VERSION 5.8 ;
BUSBITCHARS "[]" ;
DIVIDERCHAR "/" ;
UNITS
    DATABASE MICRONS 1000 ;
END UNITS

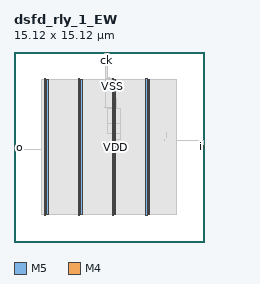
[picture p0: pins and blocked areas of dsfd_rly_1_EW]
MACRO dsfd_rly_1_EW
  FOREIGN dsfd_rly_1_EW 0 0 ;
  CLASS BLOCK ;
  SIZE 15.12 BY 15.12 ;
  PIN ck
    DIRECTION INPUT ;
    USE SIGNAL ;
    PORT
      LAYER M5 ;
        RECT  7.344 15.036 7.368 15.12 ;
    END
  END ck
  PIN i
    DIRECTION INPUT ;
    USE SIGNAL ;
    PORT
      LAYER M4 ;
        RECT  15.036 7.536 15.12 7.56 ;
    END
    PORT
      LAYER M4 ;
        RECT  15.001 7.536 15.084 7.656 ;
    END
  END i
  PIN o
    DIRECTION OUTPUT ;
    USE SIGNAL ;
    PORT
      LAYER M4 ;
        RECT  0 7.536 0.084 7.56 ;
    END
    PORT
      LAYER M4 ;
        RECT  0.06 7.536 0.137 7.56 ;
    END
  END o
  PIN rs
    DIRECTION INPUT ;
    USE SIGNAL ;
    PORT
      LAYER M5 ;
        RECT  7.44 15.036 7.464 15.12 ;
    END
  END rs
  PIN VDD
    DIRECTION INOUT ;
    USE POWER ;
    PORT
      LAYER M5 ;
        RECT  10.692 2.151 10.812 12.969 ;
        RECT  7.992 2.151 8.112 12.969 ;
        RECT  5.292 2.151 5.412 12.969 ;
        RECT  2.592 2.151 2.712 12.969 ;
    END
  END VDD
  PIN VSS
    DIRECTION INOUT ;
    USE GROUND ;
    PORT
      LAYER M5 ;
        RECT  10.5 2.137 10.62 12.983 ;
        RECT  7.8 2.137 7.92 12.983 ;
        RECT  5.1 2.137 5.22 12.983 ;
        RECT  2.4 2.137 2.52 12.983 ;
    END
  END VSS
  OBS
    LAYER RVTN ;
     RECT  2.16 2.16 12.96 2.295 ;
     RECT  2.16 2.565 12.96 2.835 ;
     RECT  2.16 3.105 12.96 3.375 ;
     RECT  2.16 3.645 12.96 3.915 ;
     RECT  2.16 4.185 12.96 4.455 ;
     RECT  2.16 4.725 12.96 4.995 ;
     RECT  2.16 5.265 12.96 5.535 ;
     RECT  2.16 5.805 12.96 6.075 ;
     RECT  2.16 6.345 12.96 6.615 ;
     RECT  2.16 6.885 12.96 7.155 ;
     RECT  2.16 7.425 12.96 7.695 ;
     RECT  2.16 7.965 12.96 8.235 ;
     RECT  2.16 8.505 12.96 8.775 ;
     RECT  2.16 9.045 12.96 9.315 ;
     RECT  2.16 9.585 12.96 9.855 ;
     RECT  2.16 10.125 12.96 10.395 ;
     RECT  2.16 10.665 12.96 10.935 ;
     RECT  2.16 11.205 12.96 11.475 ;
     RECT  2.16 11.745 12.96 12.015 ;
     RECT  2.16 12.285 12.96 12.555 ;
     RECT  2.16 12.825 12.96 12.96 ;
    LAYER RVTP ;
     RECT  2.16 2.295 12.96 2.565 ;
     RECT  2.16 2.835 12.96 3.105 ;
     RECT  2.16 3.375 12.96 3.645 ;
     RECT  2.16 3.915 12.96 4.185 ;
     RECT  2.16 4.455 12.96 4.725 ;
     RECT  2.16 4.995 12.96 5.265 ;
     RECT  2.16 5.535 12.96 5.805 ;
     RECT  2.16 6.075 12.96 6.345 ;
     RECT  2.16 6.615 12.96 6.885 ;
     RECT  2.16 7.155 12.96 7.425 ;
     RECT  2.16 7.695 12.96 7.965 ;
     RECT  2.16 8.235 12.96 8.505 ;
     RECT  2.16 8.775 12.96 9.045 ;
     RECT  2.16 9.315 12.96 9.585 ;
     RECT  2.16 9.855 12.96 10.125 ;
     RECT  2.16 10.395 12.96 10.665 ;
     RECT  2.16 10.935 12.96 11.205 ;
     RECT  2.16 11.475 12.96 11.745 ;
     RECT  2.16 12.015 12.96 12.285 ;
     RECT  2.16 12.555 12.96 12.825 ;
    LAYER M1 ;
     RECT  2.16 2.151 12.96 12.969 ;
    LAYER M2 ;
     RECT  0.103 7.326 2.16 7.344 ;
     RECT  2.16 2.151 12.96 12.969 ;
     RECT  12.96 8.046 15.107 8.064 ;
    LAYER M3 ;
     RECT  2.415 2.143 2.505 2.413 ;
     RECT  5.115 2.143 5.205 2.413 ;
     RECT  7.815 2.143 7.905 2.413 ;
     RECT  10.515 2.143 10.605 2.413 ;
     RECT  0.108 7.321 0.126 7.565 ;
     RECT  15.012 7.531 15.03 7.627 ;
     RECT  15.012 7.627 15.102 7.661 ;
     RECT  15.084 7.661 15.102 8.069 ;
     RECT  7.815 2.413 8.097 8.131 ;
     RECT  11.988 8.041 12.006 8.195 ;
     RECT  7.815 8.131 8.442 8.671 ;
     RECT  12.096 8.311 12.114 8.735 ;
     RECT  7.416 8.671 8.442 9.391 ;
     RECT  7.416 9.391 8.514 10.589 ;
     RECT  7.416 10.589 8.154 10.669 ;
     RECT  7.2 10.669 8.154 10.733 ;
     RECT  7.815 10.733 8.154 11.399 ;
     RECT  7.815 11.399 8.097 11.933 ;
     RECT  2.415 2.413 2.697 12.707 ;
     RECT  5.115 2.413 5.397 12.707 ;
     RECT  7.704 11.933 8.097 12.707 ;
     RECT  10.515 2.413 10.797 12.707 ;
     RECT  7.704 12.707 7.905 12.865 ;
     RECT  2.415 12.707 2.505 12.977 ;
     RECT  5.115 12.707 5.205 12.977 ;
     RECT  7.596 12.865 7.905 12.977 ;
     RECT  10.515 12.707 10.605 12.977 ;
     RECT  7.596 12.977 7.614 13.085 ;
    LAYER M4 ;
     RECT  2.408 2.148 2.512 12.972 ;
     RECT  2.512 2.418 2.704 12.702 ;
     RECT  5.108 2.148 5.212 12.972 ;
     RECT  5.212 2.418 5.404 12.702 ;
     RECT  7.237 14.976 7.379 15 ;
     RECT  7.429 13.056 7.625 13.08 ;
     RECT  7.189 10.704 7.808 10.728 ;
     RECT  7.808 2.148 7.912 12.972 ;
     RECT  7.912 2.418 8.104 12.702 ;
     RECT  10.508 2.148 10.612 12.972 ;
     RECT  10.612 2.418 10.804 12.702 ;
     RECT  15.084 7.632 15.113 7.656 ;
    LAYER M5 ;
     RECT  2.4 2.137 2.52 2.151 ;
     RECT  5.1 2.137 5.22 2.151 ;
     RECT  7.8 2.137 7.92 2.151 ;
     RECT  10.5 2.137 10.62 2.151 ;
     RECT  7.8 2.151 8.112 10.693 ;
     RECT  2.4 2.151 2.712 12.969 ;
     RECT  5.1 2.151 5.412 12.969 ;
     RECT  7.248 10.693 8.112 12.969 ;
     RECT  10.5 2.151 10.812 12.969 ;
     RECT  2.4 12.969 2.52 12.983 ;
     RECT  5.1 12.969 5.22 12.983 ;
     RECT  7.248 12.969 7.92 12.983 ;
     RECT  10.5 12.969 10.62 12.983 ;
     RECT  7.248 12.983 7.464 15.011 ;
     RECT  7.344 15.011 7.464 15.056 ;
  END
END dsfd_rly_1_EW
END LIBRARY
